VERSION 5.7 ;
  NOWIREEXTENSIONATPIN ON ;
  DIVIDERCHAR "/" ;
  BUSBITCHARS "[]" ;
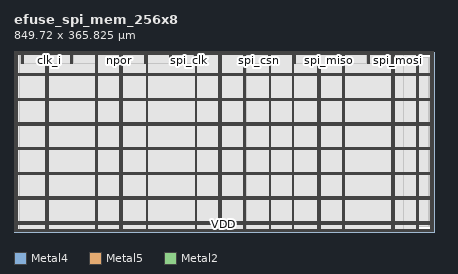
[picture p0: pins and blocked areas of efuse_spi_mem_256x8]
MACRO efuse_spi_mem_256x8
  CLASS BLOCK ;
  FOREIGN efuse_spi_mem_256x8 ;
  ORIGIN 0.000 0.000 ;
  SIZE 849.720 BY 365.825 ;
  PIN VDD
    DIRECTION INOUT ;
    USE POWER ;
    PORT
      LAYER Metal4 ;
        RECT 4.080 2.760 6.080 361.800 ;
    END
    PORT
      LAYER Metal5 ;
        RECT 4.080 2.760 845.440 4.760 ;
    END
    PORT
      LAYER Metal5 ;
        RECT 4.080 359.800 845.440 361.800 ;
    END
    PORT
      LAYER Metal4 ;
        RECT 843.440 2.760 845.440 361.800 ;
    END
    PORT
      LAYER Metal4 ;
        RECT 14.280 0.260 15.880 4.440 ;
    END
    PORT
      LAYER Metal4 ;
        RECT 14.280 341.385 15.880 364.300 ;
    END
    PORT
      LAYER Metal4 ;
        RECT 64.280 0.260 65.880 364.300 ;
    END
    PORT
      LAYER Metal4 ;
        RECT 114.280 0.260 115.880 4.440 ;
    END
    PORT
      LAYER Metal4 ;
        RECT 114.280 340.760 115.880 364.300 ;
    END
    PORT
      LAYER Metal4 ;
        RECT 164.280 0.260 165.880 364.300 ;
    END
    PORT
      LAYER Metal4 ;
        RECT 214.280 0.260 215.880 364.300 ;
    END
    PORT
      LAYER Metal4 ;
        RECT 264.280 0.260 265.880 4.440 ;
    END
    PORT
      LAYER Metal4 ;
        RECT 264.280 341.385 265.880 364.300 ;
    END
    PORT
      LAYER Metal4 ;
        RECT 314.280 0.260 315.880 4.440 ;
    END
    PORT
      LAYER Metal4 ;
        RECT 314.280 340.760 315.880 364.300 ;
    END
    PORT
      LAYER Metal4 ;
        RECT 364.280 0.260 365.880 4.440 ;
    END
    PORT
      LAYER Metal4 ;
        RECT 364.280 341.385 365.880 364.300 ;
    END
    PORT
      LAYER Metal4 ;
        RECT 414.280 0.260 415.880 364.300 ;
    END
    PORT
      LAYER Metal4 ;
        RECT 464.280 0.260 465.880 364.300 ;
    END
    PORT
      LAYER Metal4 ;
        RECT 514.280 0.260 515.880 4.440 ;
    END
    PORT
      LAYER Metal4 ;
        RECT 514.280 340.760 515.880 364.300 ;
    END
    PORT
      LAYER Metal4 ;
        RECT 564.280 0.260 565.880 364.300 ;
    END
    PORT
      LAYER Metal4 ;
        RECT 614.280 0.260 615.880 364.300 ;
    END
    PORT
      LAYER Metal4 ;
        RECT 664.280 0.260 665.880 364.300 ;
    END
    PORT
      LAYER Metal4 ;
        RECT 714.280 0.260 715.880 4.440 ;
    END
    PORT
      LAYER Metal4 ;
        RECT 714.280 340.760 715.880 364.300 ;
    END
    PORT
      LAYER Metal4 ;
        RECT 764.280 0.260 765.880 364.300 ;
    END
    PORT
      LAYER Metal4 ;
        RECT 814.280 0.260 815.880 364.300 ;
    END
    PORT
      LAYER Metal5 ;
        RECT 1.580 15.960 847.940 17.560 ;
    END
    PORT
      LAYER Metal5 ;
        RECT 1.580 65.960 847.940 67.560 ;
    END
    PORT
      LAYER Metal5 ;
        RECT 1.580 115.960 847.940 117.560 ;
    END
    PORT
      LAYER Metal5 ;
        RECT 1.580 165.960 847.940 167.560 ;
    END
    PORT
      LAYER Metal5 ;
        RECT 1.580 215.960 847.940 217.560 ;
    END
    PORT
      LAYER Metal5 ;
        RECT 1.580 265.960 847.940 267.560 ;
    END
    PORT
      LAYER Metal5 ;
        RECT 1.580 315.960 847.940 317.560 ;
    END
  END VDD
  PIN VSS
    DIRECTION INOUT ;
    USE GROUND ;
    PORT
      LAYER Metal4 ;
        RECT 1.580 0.260 3.580 364.300 ;
    END
    PORT
      LAYER Metal5 ;
        RECT 1.580 0.260 847.940 2.260 ;
    END
    PORT
      LAYER Metal5 ;
        RECT 1.580 362.300 847.940 364.300 ;
    END
    PORT
      LAYER Metal4 ;
        RECT 845.940 0.260 847.940 364.300 ;
    END
    PORT
      LAYER Metal4 ;
        RECT 17.580 0.260 19.180 4.440 ;
    END
    PORT
      LAYER Metal4 ;
        RECT 17.580 340.740 19.180 364.300 ;
    END
    PORT
      LAYER Metal4 ;
        RECT 67.580 0.260 69.180 364.300 ;
    END
    PORT
      LAYER Metal4 ;
        RECT 117.580 0.260 119.180 4.440 ;
    END
    PORT
      LAYER Metal4 ;
        RECT 117.580 340.740 119.180 364.300 ;
    END
    PORT
      LAYER Metal4 ;
        RECT 167.580 0.260 169.180 364.300 ;
    END
    PORT
      LAYER Metal4 ;
        RECT 217.580 0.260 219.180 364.300 ;
    END
    PORT
      LAYER Metal4 ;
        RECT 267.580 0.260 269.180 364.300 ;
    END
    PORT
      LAYER Metal4 ;
        RECT 317.580 0.260 319.180 4.440 ;
    END
    PORT
      LAYER Metal4 ;
        RECT 317.580 340.740 319.180 364.300 ;
    END
    PORT
      LAYER Metal4 ;
        RECT 367.580 0.260 369.180 364.300 ;
    END
    PORT
      LAYER Metal4 ;
        RECT 417.580 0.260 419.180 364.300 ;
    END
    PORT
      LAYER Metal4 ;
        RECT 467.580 0.260 469.180 364.300 ;
    END
    PORT
      LAYER Metal4 ;
        RECT 517.580 0.260 519.180 364.300 ;
    END
    PORT
      LAYER Metal4 ;
        RECT 567.580 0.260 569.180 4.440 ;
    END
    PORT
      LAYER Metal4 ;
        RECT 567.580 341.385 569.180 364.300 ;
    END
    PORT
      LAYER Metal4 ;
        RECT 617.580 0.260 619.180 364.300 ;
    END
    PORT
      LAYER Metal4 ;
        RECT 667.580 0.260 669.180 364.300 ;
    END
    PORT
      LAYER Metal4 ;
        RECT 717.580 0.260 719.180 4.440 ;
    END
    PORT
      LAYER Metal4 ;
        RECT 717.580 341.385 719.180 364.300 ;
    END
    PORT
      LAYER Metal4 ;
        RECT 767.580 0.260 769.180 364.300 ;
    END
    PORT
      LAYER Metal4 ;
        RECT 817.580 0.260 819.180 364.300 ;
    END
    PORT
      LAYER Metal5 ;
        RECT 1.580 19.260 847.940 20.860 ;
    END
    PORT
      LAYER Metal5 ;
        RECT 1.580 69.260 847.940 70.860 ;
    END
    PORT
      LAYER Metal5 ;
        RECT 1.580 119.260 847.940 120.860 ;
    END
    PORT
      LAYER Metal5 ;
        RECT 1.580 169.260 847.940 170.860 ;
    END
    PORT
      LAYER Metal5 ;
        RECT 1.580 219.260 847.940 220.860 ;
    END
    PORT
      LAYER Metal5 ;
        RECT 1.580 269.260 847.940 270.860 ;
    END
    PORT
      LAYER Metal5 ;
        RECT 1.580 319.260 847.940 320.860 ;
    END
  END VSS
  PIN clk_i
    DIRECTION INPUT ;
    USE SIGNAL ;
    ANTENNAGATEAREA 4.408000 ;
    ANTENNADIFFAREA 0.410400 ;
    PORT
      LAYER Metal2 ;
        RECT 71.680 365.265 72.240 365.825 ;
    END
  END clk_i
  PIN npor
    DIRECTION INPUT ;
    USE SIGNAL ;
    ANTENNAGATEAREA 4.408000 ;
    ANTENNADIFFAREA 0.410400 ;
    PORT
      LAYER Metal2 ;
        RECT 212.800 365.265 213.360 365.825 ;
    END
  END npor
  PIN spi_clk
    DIRECTION INPUT ;
    USE SIGNAL ;
    ANTENNAGATEAREA 1.102000 ;
    ANTENNADIFFAREA 0.410400 ;
    PORT
      LAYER Metal2 ;
        RECT 353.920 365.265 354.480 365.825 ;
    END
  END spi_clk
  PIN spi_csn
    DIRECTION INPUT ;
    USE SIGNAL ;
    ANTENNAGATEAREA 1.102000 ;
    ANTENNADIFFAREA 0.410400 ;
    PORT
      LAYER Metal2 ;
        RECT 495.040 365.265 495.600 365.825 ;
    END
  END spi_csn
  PIN spi_miso
    DIRECTION OUTPUT ;
    USE SIGNAL ;
    ANTENNADIFFAREA 4.818400 ;
    PORT
      LAYER Metal2 ;
        RECT 636.160 365.265 636.720 365.825 ;
    END
  END spi_miso
  PIN spi_mosi
    DIRECTION INPUT ;
    USE SIGNAL ;
    ANTENNAGATEAREA 1.102000 ;
    ANTENNADIFFAREA 0.410400 ;
    PORT
      LAYER Metal2 ;
        RECT 777.280 365.265 777.840 365.825 ;
    END
  END spi_mosi
  OBS
      LAYER Nwell ;
        RECT 9.650 11.330 839.870 353.230 ;
      LAYER Metal1 ;
        RECT 10.080 11.460 839.440 353.100 ;
      LAYER Metal2 ;
        RECT 7.980 364.965 71.380 365.265 ;
        RECT 72.540 364.965 212.500 365.265 ;
        RECT 213.660 364.965 353.620 365.265 ;
        RECT 354.780 364.965 494.740 365.265 ;
        RECT 495.900 364.965 635.860 365.265 ;
        RECT 637.020 364.965 776.980 365.265 ;
        RECT 778.140 364.965 819.040 365.265 ;
        RECT 7.980 2.330 819.040 364.965 ;
      LAYER Metal3 ;
        RECT 7.930 1.820 819.090 361.620 ;
      LAYER Metal4 ;
        RECT 10.240 341.085 13.980 358.310 ;
        RECT 16.180 341.085 17.280 358.310 ;
        RECT 10.240 340.440 17.280 341.085 ;
        RECT 19.480 340.440 63.980 358.310 ;
        RECT 10.240 4.740 63.980 340.440 ;
        RECT 10.240 1.770 13.980 4.740 ;
        RECT 16.180 1.770 17.280 4.740 ;
        RECT 19.480 1.770 63.980 4.740 ;
        RECT 66.180 1.770 67.280 358.310 ;
        RECT 69.480 340.460 113.980 358.310 ;
        RECT 116.180 340.460 117.280 358.310 ;
        RECT 69.480 340.440 117.280 340.460 ;
        RECT 119.480 340.440 163.980 358.310 ;
        RECT 69.480 4.740 163.980 340.440 ;
        RECT 69.480 1.770 113.980 4.740 ;
        RECT 116.180 1.770 117.280 4.740 ;
        RECT 119.480 1.770 163.980 4.740 ;
        RECT 166.180 1.770 167.280 358.310 ;
        RECT 169.480 1.770 213.980 358.310 ;
        RECT 216.180 1.770 217.280 358.310 ;
        RECT 219.480 341.085 263.980 358.310 ;
        RECT 266.180 341.085 267.280 358.310 ;
        RECT 219.480 4.740 267.280 341.085 ;
        RECT 219.480 1.770 263.980 4.740 ;
        RECT 266.180 1.770 267.280 4.740 ;
        RECT 269.480 340.460 313.980 358.310 ;
        RECT 316.180 340.460 317.280 358.310 ;
        RECT 269.480 340.440 317.280 340.460 ;
        RECT 319.480 341.085 363.980 358.310 ;
        RECT 366.180 341.085 367.280 358.310 ;
        RECT 319.480 340.440 367.280 341.085 ;
        RECT 269.480 4.740 367.280 340.440 ;
        RECT 269.480 1.770 313.980 4.740 ;
        RECT 316.180 1.770 317.280 4.740 ;
        RECT 319.480 1.770 363.980 4.740 ;
        RECT 366.180 1.770 367.280 4.740 ;
        RECT 369.480 1.770 413.980 358.310 ;
        RECT 416.180 1.770 417.280 358.310 ;
        RECT 419.480 1.770 463.980 358.310 ;
        RECT 466.180 1.770 467.280 358.310 ;
        RECT 469.480 340.460 513.980 358.310 ;
        RECT 516.180 340.460 517.280 358.310 ;
        RECT 469.480 4.740 517.280 340.460 ;
        RECT 469.480 1.770 513.980 4.740 ;
        RECT 516.180 1.770 517.280 4.740 ;
        RECT 519.480 1.770 563.980 358.310 ;
        RECT 566.180 341.085 567.280 358.310 ;
        RECT 569.480 341.085 613.980 358.310 ;
        RECT 566.180 4.740 613.980 341.085 ;
        RECT 566.180 1.770 567.280 4.740 ;
        RECT 569.480 1.770 613.980 4.740 ;
        RECT 616.180 1.770 617.280 358.310 ;
        RECT 619.480 1.770 663.980 358.310 ;
        RECT 666.180 1.770 667.280 358.310 ;
        RECT 669.480 340.460 713.980 358.310 ;
        RECT 716.180 341.085 717.280 358.310 ;
        RECT 719.480 341.085 763.980 358.310 ;
        RECT 716.180 340.460 763.980 341.085 ;
        RECT 669.480 4.740 763.980 340.460 ;
        RECT 669.480 1.770 713.980 4.740 ;
        RECT 716.180 1.770 717.280 4.740 ;
        RECT 719.480 1.770 763.980 4.740 ;
        RECT 766.180 1.770 767.280 358.310 ;
        RECT 769.480 1.770 788.880 358.310 ;
  END
END efuse_spi_mem_256x8
END LIBRARY

